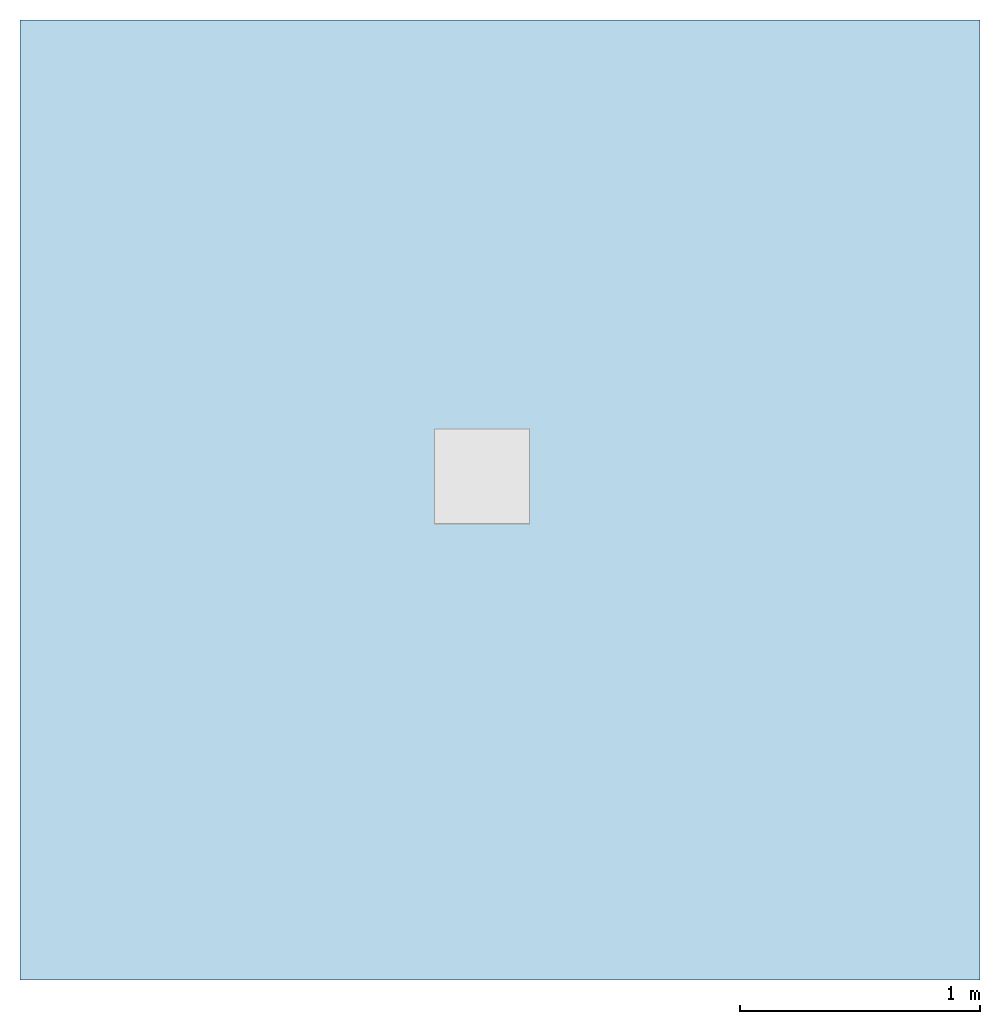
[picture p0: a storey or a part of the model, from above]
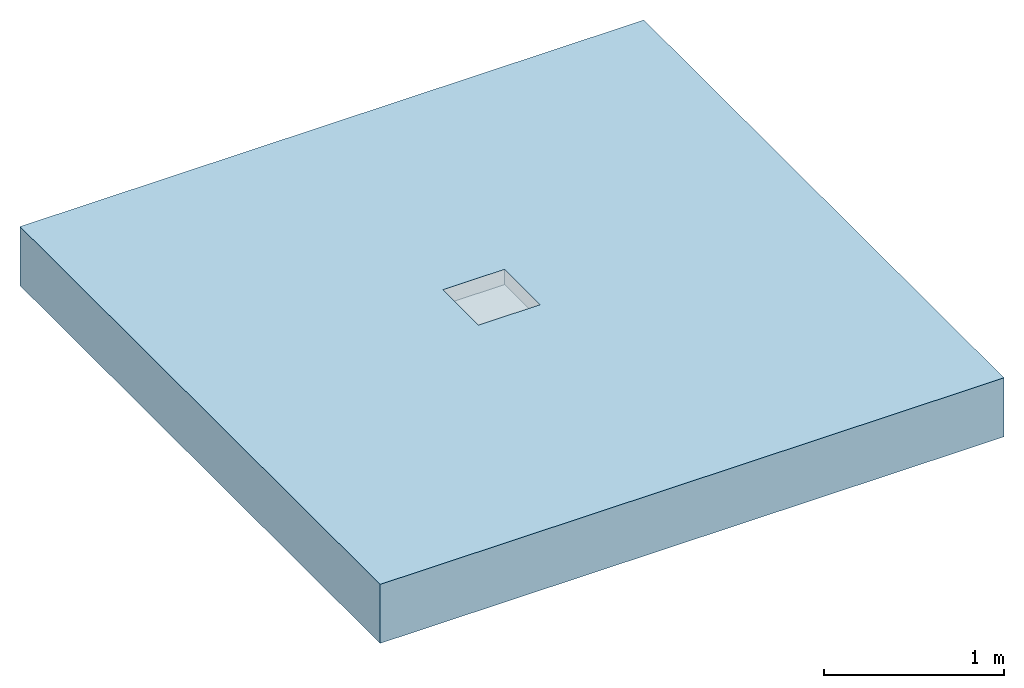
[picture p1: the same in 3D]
Properties of the parts of a building model (IFC2X3)

# File
Description: ViewDefinition [CoordinationView]
File name: Project Number
Time: 2014-06-06T11:11:14
Written by: The EXPRESS Data Manager Version 5.01.0100.02.64mod : 6 Jun 2012
Made in: 20130308_1515(x64) - Exporter 2014.0.2013.0308 - Default UI
Comment: STEP Physical File produced by: The EXPRESS Data Manager Version 5.01.0100.02.64mod : 6 Jun 2012 * Module: EDMstepFileFactory/EDMstandAlone * Creation date: Fri Jun 06 11:11:14 2014 * Host: IN-BLR-PC-0010 * Database: C:\Users\palleri\AppData\Local\Temp\{17221322-ACC7-484F-B521-1614CAE6B639}\ifc * Database version: 5507 * Database creation date: Fri Jun 06 11:11:13 2014 * Schema: IFC2X3 * Model: DataRepository.ifc * Model creation date: Fri Jun 06 11:11:14 2014 * Header model: DataRepository.ifc_HeaderModel * Header model creation date: Fri Jun 06 11:11:14 2014 * EDMuser: sdai-user * EDMgroup: sdai-group * License ID and type: 5605 : Permanent license. Expiry date: * EDMstepFileFactory options: 020000

# IfcProject, Project Number
LongName: Project Name; Phase: Project Status

# IfcSite, Default
RefLatitude: 42, 21, 30, 344238; RefLongitude: -71, -3, -35, -194702; RefElevation: 0 mm

# IfcBuilding
Pset_BuildingCommon - NumberOfStoreys: 1
Other - Client Name: Owner; Project Number: Project Number; Project Address: ## Street City, State Zip; Project Name: Project Name; Project Issue Date: Issue Date; Project Status: Project Status

# IfcBuildingStorey, Level 1
LongName: Level 1; Elevation: 0 mm
Graphics - Line Pattern: Center; Color: 0; Symbol at End 1 Default: no; Symbol: M_Level Head - Circle: M_Level Head - Circle; Line Weight: 1; Symbol at End 2 Default: yes
Constraints - Elevation Base: Project Base Point; Elevation: 0 mm
Dimensions - Computation Height: 0 mm
Identity Data - Building Story: yes; Structural: no; Name: Level 1

# IfcFlowTerminal: 38156 - Access Frame - Fixed Height - Invert Depth 50mm, ACO Freedeck Access Frame & Drain Duct (Accessories part 1) V1.27 - SS:38156 - Access Frame - Fixed Height - Invert Depth 50mm:278221
In: Level 1
Material: Stainless Steel Grade 304
Model Properties - Access Frame Extension Product Code 38687: N/A; Access Grating Product Code 36760: Load Class A15 - Mesh Grating - 14mm x 30mm Mesh - Stainless Steel 304 - 3.5kg; Access Frame Extension Product Code 38685: N/A; Access Frame Extension Product Code 38688: Load Class A15 - Access Frame Extension - Stainless Steel 304 - Invert Depth 75mm - 1.9kg; Access Frame Extension Product Code 38686: Load Class A15 - Access Frame Extension - Stainless Steel 304 - Invert Depth 50mm - 1.3kg; Access Grating Product Code 36754: N/A
Constraints - Moves With Nearby Elements: no; Level: Level: Level 1
Other - Access Frame Extension_Invert Depth 75mm: yes; Access Frame Extension: yes; Adjustable Access Frame Position Height: 105 mm; Fixed Access Frame Position Height: 105 mm; Drain Duct Vertical Height: 5000 mm; Extension Removal Void: -2 mm; Access Frame Extension_Invert Depth 50mm: no; Access Frame Extension Height: 75 mm; Access Frame Fixed Height: yes; Drain Duct: no; Top void Size: 400 mm; Access Frame Adjustable Height: no; Grating: yes
Dimensions - Total Height: 159 mm; Drainage Duct – Level below FFL: 30 mm; Top Void Height Start: -105 mm; Base Height: 3000 mm; Access Frame Extension Position Height: 0 mm; Top Void Height End: -55 mm; Height for Adjustable Access Frame: 105 mm; Grating Start: 0 mm; Grating End: -20 mm; Drain Duct End: -100 mm
Phasing - Phase Created: New Construction
Construction - 38686_Access Frame Extension_Stainless Steel_Invert Depth 50mm: no; 36760_Access Grating_Mesh Grating_Stainless Steel 304: yes; 38688_Access Frame Extension_Stainless Steel_Invert Depth 75mm: yes
Identity Data - Mark: 15; Watermark2: This file is water marked and users are prohibited to reproduce, adapt, distribute this information; Watermark1: This file is the property of ACO Technologies PLC; Address: ACO Business Centre, Caxton Road, Bedford, MK41 0LF; Fax: +44 (0)1462 851490; Telephone: +44 (0)1462 816666; Watermarked By: www.acobd.com; Website: www.acobd.com; Manufacturer: ACO Building Drainage; Watermarked With: BIM Manager Premium Suite; E-mail Technical: abdtechnical@aco.co.uk; E-mail Sales: abdcommercial@aco.co.uk
Pset_ManufacturerTypeInformation - Manufacturer: ACO Building Drainage
General - Product Code: 38156; Channel Material: Stainless Steel Grade 304; Channel Colour: Mid Grey; Channel Recycled Material Content: 60 - 70 %; NBS Specification: NBS Section R10 Gravity Rainwater Drainage Systems, Subsection 365; Dimensions (LxWxH): 400 x 400 x 50; Weight (Kg): 5.7kg; Maintenance Guidelines: X:\Electronic Literature\ABD Electronic Literature\Roof and Balcony Drainage\ACO Freedeck Brochure.pdf; Product Standard: BS EN 1433:2002, CE marked; Product Description: ACO Freedeck Access Frame - Fixed Height; Price: POA - contact ACO; Product Type: Linear Deck Drainage System; Product Range: ACO Freedeck; Channel Recyclable: Fully recyclable; Installation Guidelines: X:\Electronic Literature\ABD Electronic Literature\Roof and Balcony Drainage\ACO Freedeck Brochure.pdf; Load Class: A15
Materials and Finishes - Material: Stainless Steel Grade 304

# IfcOpeningElement: Recess (3)
In: Level 1
Dimensions - Area: 16 m2; Volume: 6.38342 m3; Perimeter: 16000 mm; Thickness: 400 mm
Constraints - Height Offset From Level: 0 mm; Level: Level: Level 1; Room Bounding: yes; Related to Mass: no
Structural - Enable Analytical Model: no; Structural: no
Phasing - Phase Created: New Construction
Graphics - Coarse Scale Fill Color: 0
Construction - Function: Interior; Default Thickness: 400 mm
Analytical Properties - Thermal mass: 604440; Heat Transfer Coefficient (U): 2.615; Roughness: 1; Absorptance: 0.1; Thermal Resistance (R): 0.382409
Materials and Finishes - Structural Material: Concrete, Broom Finish

# IfcSlab: Floor:Generic Floor - 400mm, Floor:Generic Floor - 400mm:193825
In: Level 1
PredefinedType: FLOOR; Material: Concrete, Broom Finish 400 mm
Dimensions - Area: 16 m2; Volume: 6.38342 m3; Perimeter: 16000 mm; Thickness: 400 mm
Constraints - Height Offset From Level: 0 mm; Level: Level: Level 1; Room Bounding: yes; Related to Mass: no
Structural - Enable Analytical Model: no; Structural: no
Phasing - Phase Created: New Construction
Pset_SlabCommon - Reference: Generic Floor - 400mm; IsExternal: no; LoadBearing: yes; ThermalTransmittance: 2.615 kg/K/s3
Graphics - Coarse Scale Fill Color: 0
Construction - Function: Interior; Default Thickness: 400 mm
Analytical Properties - Thermal mass: 604440; Heat Transfer Coefficient (U): 2.615; Roughness: 1; Absorptance: 0.1; Thermal Resistance (R): 0.382409
Materials and Finishes - Structural Material: Concrete, Broom Finish
